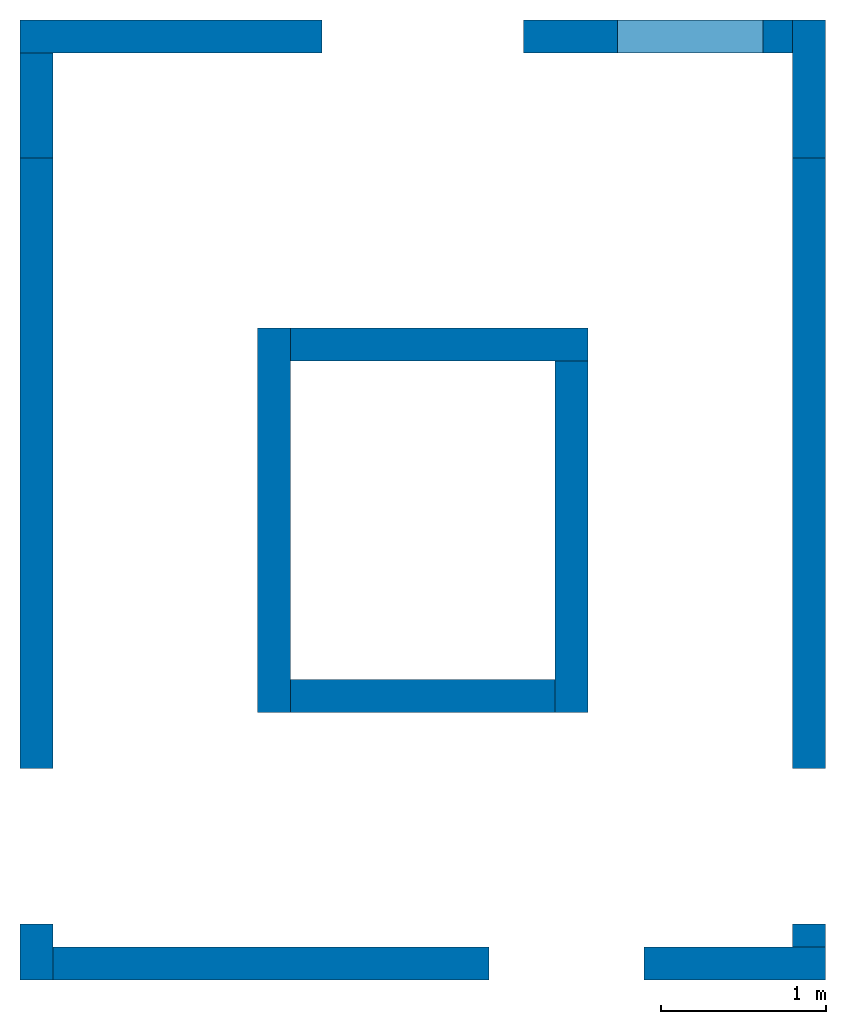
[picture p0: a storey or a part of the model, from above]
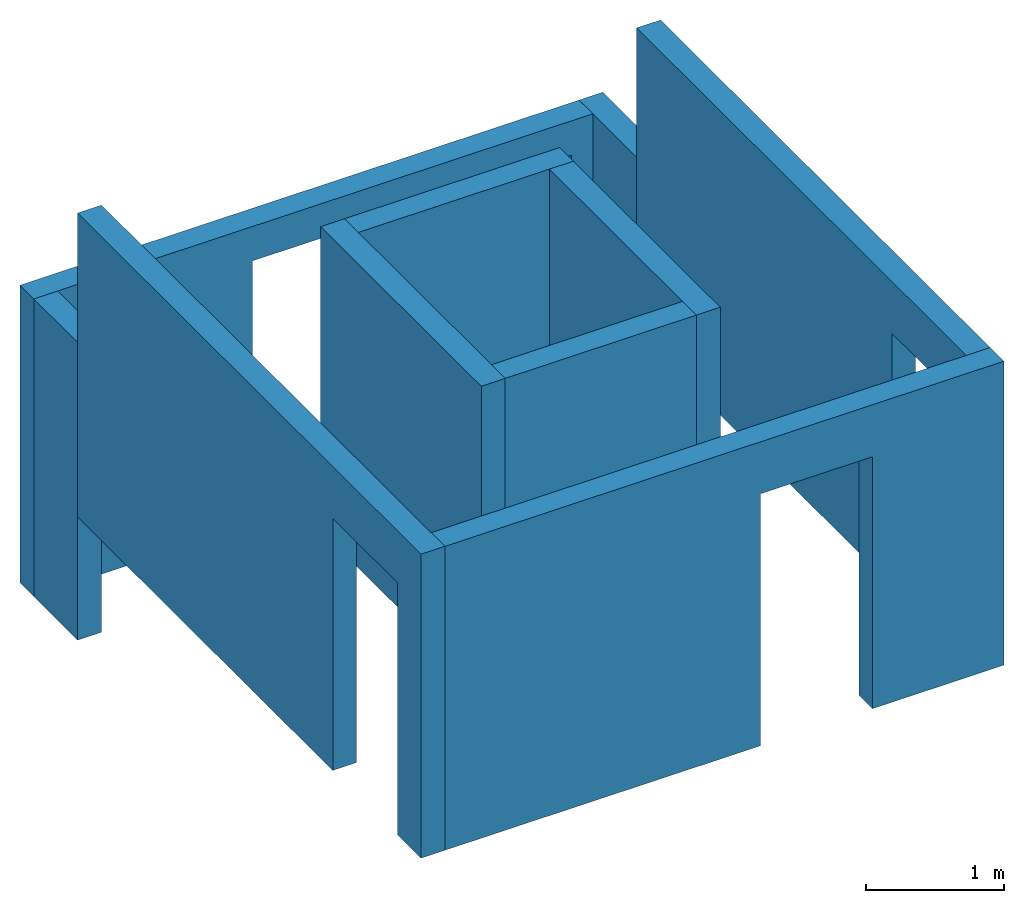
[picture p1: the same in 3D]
Properties of the parts of a building model (IFC2X3)

# File
Description: no view
File name: A.ifc
Time: 2026-08-27T15:49:46
Author: Besar Asani
Organization: No Organization
Written by: ODA SDAI 25.4
Authorization: b.asani

# IfcProject, 00'000 - Besar Asani
AllplanAttributes - Bauherr: Bauherr Name; Architekt: Architekt Name; Bauort: PLZ und Ort; Bauunternehmer Straße: Bauunternehmer Strasse; Bauunternehmer Plz/Ort: Bauunternehmer PLZ Ort; Bauherr Straße: Bauherr Strasse; Bauherr Plz/Ort: Bauherr PLZ Ort; Architekt Straße: Architekt Strasse; Architekt Plz/Ort: Architekt PLZ Ort; Projektbeschreibung: Projektbeschreibung; Bauunternehmer: Bauunternehmer Name

# IfcBuildingStorey, A
In: Gebäude
Elevation: 0 m

# IfcOpeningElement: Opening (5)
In: A
AllplanAttributes - Object Layer Attributes #1, Status: Neubau; Object Layer Attributes #1, Versatz_oben: 0; Object Layer Attributes #1, Gewerk: Betonarbeiten; Object Layer Attributes #1, Türanschlag: -; Object Layer Attributes #1, Objektname: Türöffnung; Object Layer Attributes #1, Versatz_unten: 0; Object Layer Attributes #1, Abrechnungsart: m³
Name | Object Layer Attributes #1, Allright_Bauteil_ID
Fensteröffnung | 7510Fen0000000005
Fensteröffnung | 7510Fen0000000011
Fensteröffnung | 7510Fen0000000017
Fensteröffnung | 7510Fen0000000044
Fensteröffnung | 7510Fen0000000041

# IfcWallStandardCase (10)
In: A
Material: layer 0.2 m
AllplanAttributes - Einheit: m³; Objektname: Wand; Attributset-Objekt: Wall; Abrechnungsart: m³; Object Layer Attributes #1, Status: Neubau; Object Layer Attributes #1, Gewerk: Betonarbeiten; Object Layer Attributes #1, Abrechnungsart: m³; Object Layer Attributes #1, Objektname: Wand
WallCommon - Status: Neubau
Name | Allright_Bauteil_ID | Object Layer Attributes #1, Allright_Bauteil_ID | Object Layer Attributes #1, 2D interaktion
 | 7510HWa0000000002 | 7510Wa 0000000003
 | 7510HWa0000000008 | 7510Wa 0000000009
 | 7510HWa0000000014 | 7510Wa 0000000015
 | 7510HWa0000000020 | 7510Wa 0000000021 | yes
 | 7510HWa0000000023 | 7510Wa 0000000024 | yes
 | 7510HWa0000000026 | 7510Wa 0000000027 | yes
 | 7510HWa0000000029 | 7510Wa 0000000030 | yes
 | 7510HWa0000000032 | 7510Wa 0000000033 | yes
 | 7510HWa0000000035 | 7510Wa 0000000036 | yes
 | 7510HWa0000000038 | 7510Wa 0000000039 | yes
